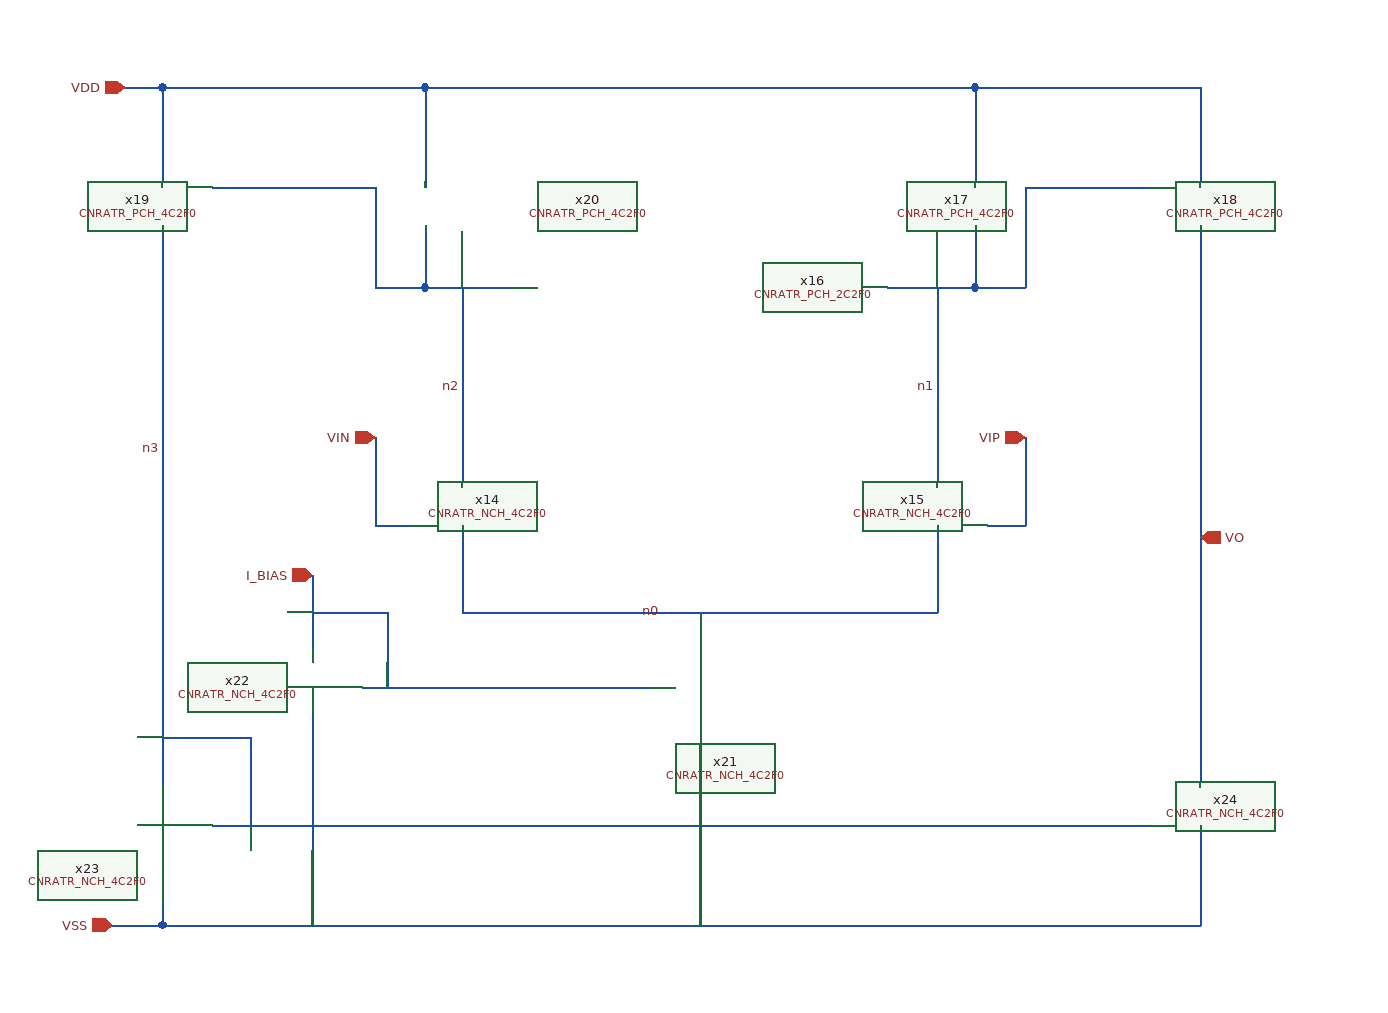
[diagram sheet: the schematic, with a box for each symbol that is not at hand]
v {xschem version=3.4.4 file_version=1.2
}
G {}
K {}
V {}
S {}
E {}
N 1990 500 1990 540 {
lab=n0}
N 1610 540 1990 540 {
lab=n0}
N 1610 500 1610 540 {
lab=n0}
N 1800 540 1800 570 {
lab=n0}
N 2020 230 2020 280 {
lab=n1}
N 1950 280 2020 280 {
lab=n1}
N 1990 280 1990 440 {
lab=n1}
N 1580 230 1580 280 {
lab=n2}
N 1580 280 1650 280 {
lab=n2}
N 1610 280 1610 440 {
lab=n2}
N 1580 120 1580 170 {
lab=VDD_1V8}
N 1580 120 2020 120 {
lab=VDD_1V8}
N 2020 120 2020 170 {
lab=VDD_1V8}
N 1580 170 1580 200 {
lab=VDD_1V8}
N 2020 170 2020 200 {
lab=VDD_1V8}
N 2060 200 2060 280 {
lab=n1}
N 2020 280 2060 280 {
lab=n1}
N 1540 200 1540 280 {
lab=n2}
N 1540 280 1580 280 {
lab=n2}
N 2060 200 2160 200 {
lab=n1}
N 1410 200 1540 200 {
lab=n2}
N 2200 230 2200 680 {
lab=VO}
N 1410 710 2160 710 {
lab=n3}
N 1370 230 1370 680 {
lab=n3}
N 1370 640 1440 640 {
lab=n3}
N 1440 640 1440 710 {
lab=n3}
N 2200 120 2200 170 {
lab=VDD_1V8}
N 2020 120 2200 120 {
lab=VDD_1V8}
N 1370 120 1370 170 {
lab=VDD_1V8}
N 1370 120 1580 120 {
lab=VDD_1V8}
N 1370 740 1370 790 {
lab=VSS}
N 1370 790 2200 790 {
lab=VSS}
N 2200 740 2200 790 {
lab=VSS}
N 1800 630 1800 790 {
lab=VSS}
N 2200 710 2200 740 {
lab=VSS}
N 1370 710 1370 740 {
lab=VSS}
N 1800 600 1800 630 {
lab=VSS}
N 1990 470 1990 500 {
lab=n0}
N 1610 470 1610 500 {
lab=n0}
N 1370 170 1370 200 {
lab=VDD_1V8}
N 2200 170 2200 200 {
lab=VDD_1V8}
N 1530 600 1760 600 {
lab=I_BIAS}
N 1490 510 1490 570 {
lab=I_BIAS}
N 1490 600 1490 630 {
lab=VSS}
N 1490 630 1490 790 {
lab=VSS}
N 1540 470 1570 470 {
lab=VIN}
N 1540 400 1540 470 {
lab=VIN}
N 2030 470 2060 470 {
lab=VIP}
N 2060 400 2060 470 {
lab=VIP}
N 1490 540 1550 540 {
lab=I_BIAS}
N 1550 540 1550 600 {
lab=I_BIAS}
N 1340 120 1370 120 {
lab=VDD_1V8}
N 1330 790 1370 790 {
lab=VSS}
C {CNR_GR02_SKY130NM/CNR_ATR_SKY130NM/CNRATR_NCH_4C2F0.sym} 1570 470 0 0 {name=x14 }
C {CNR_GR02_SKY130NM/CNR_ATR_SKY130NM/CNRATR_NCH_4C2F0.sym} 2030 470 0 1 {name=x15 }
C {CNR_GR02_SKY130NM/CNR_ATR_SKY130NM/CNRATR_PCH_2C2F0.mag} 1910 200 0 0 {name=x16 }
C {devices/ipin.sym} 1540 400 0 0 {name=p7 lab=VIN}
C {devices/ipin.sym} 2060 400 0 0 {name=p8 lab=VIP}
C {devices/opin.sym} 2200 480 0 0 {name=p9 lab=VO}
C {devices/ipin.sym} 1340 120 0 0 {name=p10 lab=VDD}
C {devices/ipin.sym} 1330 790 0 0 {name=p11 lab=VSS}
C {CNR_GR02_SKY130NM/CNR_ATR_SKY130NM/CNRATR_PCH_4C2F0.sym} 2060 200 0 1 {name=x17 }
C {CNR_GR02_SKY130NM/CNR_ATR_SKY130NM/CNRATR_PCH_4C2F0.sym} 2160 200 0 0 {name=x18 }
C {devices/lab_wire.sym} 1770 540 0 0 {name=p12 sig_type=std_logic lab=n0}
C {devices/lab_wire.sym} 1990 360 0 0 {name=p13 sig_type=std_logic lab=n1}
C {devices/lab_wire.sym} 1610 360 0 0 {name=p14 sig_type=std_logic lab=n2}
C {devices/lab_wire.sym} 1370 410 0 0 {name=p15 sig_type=std_logic lab=n3}
C {CNR_GR02_SKY130NM/CNR_ATR_SKY130NM/CNRATR_PCH_4C2F0.sym} 1410 200 0 1 {name=x19 }
C {CNR_GR02_SKY130NM/CNR_ATR_SKY130NM/CNRATR_PCH_4C2F0.sym} 1540 200 0 0 {name=x20 }
C {CNR_GR02_SKY130NM/CNR_ATR_SKY130NM/CNRATR_NCH_4C2F0.sym} 1760 600 0 0 {name=x21 }
C {CNR_GR02_SKY130NM/CNR_ATR_SKY130NM/CNRATR_NCH_4C2F0.sym} 1530 600 0 1 {name=x22 }
C {CNR_GR02_SKY130NM/CNR_ATR_SKY130NM/CNRATR_NCH_4C2F0.sym} 1410 710 0 1 {name=x23 }
C {CNR_GR02_SKY130NM/CNR_ATR_SKY130NM/CNRATR_NCH_4C2F0.sym} 2160 710 0 0 {name=x24 }
C {devices/ipin.sym} 1490 510 0 0 {name=p16 lab=I_BIAS}
